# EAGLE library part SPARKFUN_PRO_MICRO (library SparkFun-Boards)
SparkFun Pro Micro Atmega32U4 compatible footprint. SparkFun Products: 3.3V/8MHz 5V/16MHz

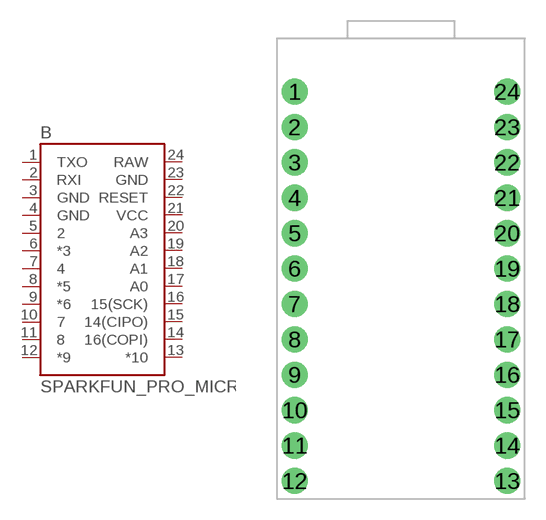
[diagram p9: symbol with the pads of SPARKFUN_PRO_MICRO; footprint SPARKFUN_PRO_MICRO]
Designator prefix B

## SPARKFUN_PRO_MICRO  [SPARKFUN_PRO_MICRO]
1  TXO
2  RXI
3  GND  pwr
4  GND  pwr
5  2
6  *3
7  4
8  *5
9  *6
10  7
11  8
12  *9
13  *10
14  16(COPI)
15  14(CIPO)
16  15(SCK)
17  A0
18  A1
19  A2
20  A3
21  VCC  pwr
22  RESET
23  GND  pwr
24  RAW  pwr

## Footprint SPARKFUN_PRO_MICRO (pad centres in mm)
SparkFun Pro Mico Footprint (with USB connector) Specifications: Pin count: 24 Pin pitch: 0.1" Area:0.7x1.3" Example device(s): SparkFun Pro Micro
drill 1.016 pad 1.88: 1 -7.62,12.7; 2 -7.62,10.16; 3 -7.62,7.62; 4 -7.62,5.08; 5 -7.62,2.54; 6 -7.62,0; 7 -7.62,-2.54; 8 -7.62,-5.08; 9 -7.62,-7.62; 10 -7.62,-10.16; 11 -7.62,-12.7; 12 -7.62,-15.24; 13 7.62,-15.24; 14 7.62,-12.7; 15 7.62,-10.16; 16 7.62,-7.62; 17 7.62,-5.08; 18 7.62,-2.54; 19 7.62,0; 20 7.62,2.54; 21 7.62,5.08; 22 7.62,7.62; 23 7.62,10.16; 24 7.62,12.7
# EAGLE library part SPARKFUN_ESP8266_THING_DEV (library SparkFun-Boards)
SparkFun Thing -Dev Board The SparkFun ESP8266 Thing Dev is a breakout and development board for the ESP8266 WiFi SoC, with an integrated FTDI USB-to-Serial chip. SparkFun Products: SparkFun ESP8266 Thing-Dev Board

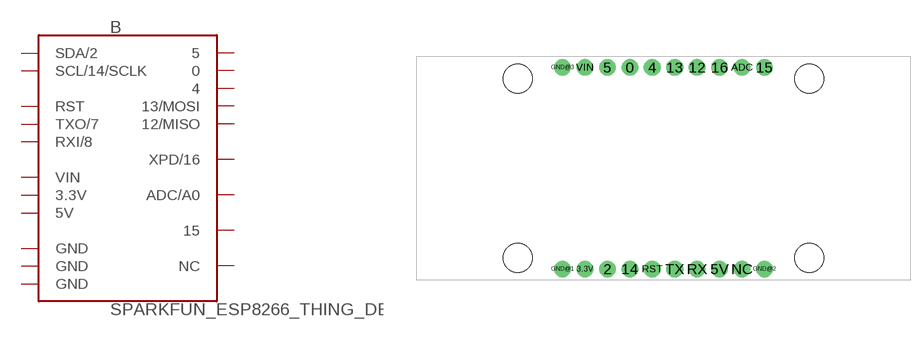
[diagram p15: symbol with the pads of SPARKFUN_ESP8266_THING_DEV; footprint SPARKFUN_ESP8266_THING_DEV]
Designator prefix B

## SPARKFUN_ESP8266_THING_DEV (SF_ID: WRL-13711)  [SPARKFUN_ESP8266_THING_DEV]
0  0
2  SDA/2
3.3V  3.3V  pwr
4  4
5  5
5V  5V  pwr
12  12/MISO
13  13/MOSI
14  SCL/14/SCLK
15  15
16  XPD/16
ADC  ADC/A0
GND@1  GND  pwr
GND@2  GND  pwr
GND@3  GND  pwr
NC  NC  nc
RST  RST  in
RX  RXI/8  in
TX  TXO/7  out
VIN  VIN  pwr

## Footprint SPARKFUN_ESP8266_THING_DEV (pad centres in mm)
SparkFun Thing Development Board Footprint Specifications: Pin count: 20 Pin pitch:0.1 inch Area: 2.2 x 1.0 inchees Example device(s): SparkFun Thing Development Board
drill 1.016 pad 1.88: 0 -2.54,11.43; 2 -5.08,-11.43; 3.3V -7.62,-11.43; 4 0,11.43; 5 -5.08,11.43; 5V 7.62,-11.43; 12 5.08,11.43; 13 2.54,11.43; 14 -2.54,-11.43; 15 12.7,11.43; 16 7.62,11.43; ADC 10.16,11.43; GND@1 -10.16,-11.43; GND@2 12.7,-11.43; GND@3 -10.16,11.43; NC 10.16,-11.43; RST 0,-11.43; RX 5.08,-11.43; TX 2.54,-11.43; VIN -7.62,11.43
hole 3.302 at -15.24,-10.16
hole 3.302 at -15.24,10.16
hole 3.302 at 17.78,10.16
hole 3.302 at 17.78,-10.16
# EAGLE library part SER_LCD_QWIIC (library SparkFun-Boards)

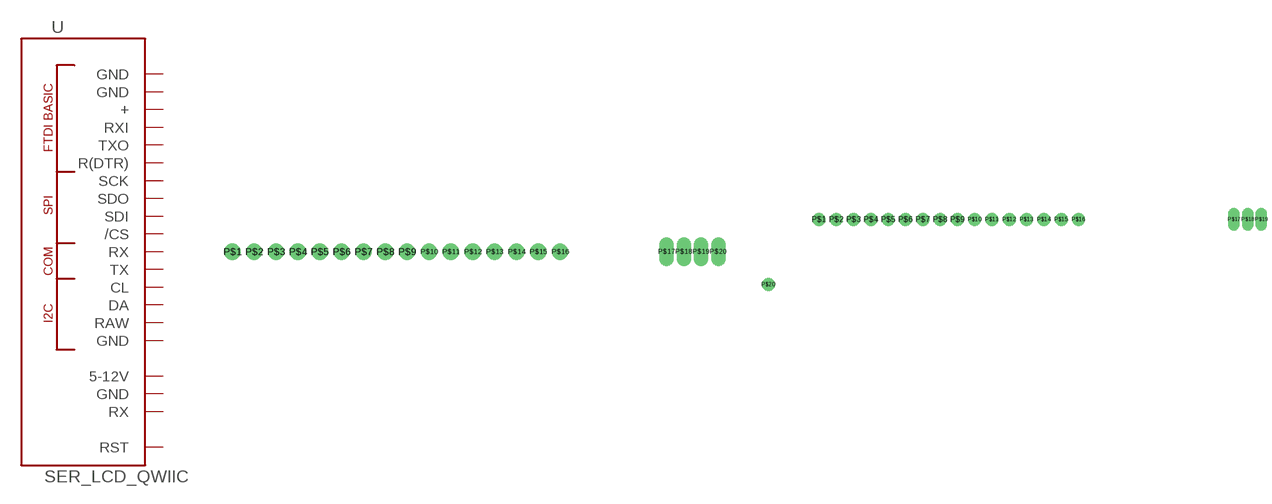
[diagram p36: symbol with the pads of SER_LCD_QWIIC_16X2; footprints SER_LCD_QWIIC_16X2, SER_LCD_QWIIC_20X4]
Designator prefix -

## SER_LCD_QWIIC16X2  [SER_LCD_QWIIC_16X2]
P$1  GND
P$2  GND
P$3  +
P$4  RXI
P$5  TXO
P$6  R(DTR)
P$7  SCK
P$8  SDO
P$9  SDI
P$10  /CS
P$11  RX
P$12  TX
P$13  CL
P$14  DA
P$15  RAW
P$16  GND
P$17  5-12V
P$18  GND
P$19  RX
P$20  RST

## SER_LCD_QWIIC20X4  [SER_LCD_QWIIC_20X4]
Pads as for SER_LCD_QWIIC_16X2

## Footprint SER_LCD_QWIIC_16X2 (pad centres in mm)
drill 1.118 pad 1.88: P$1 9.652,33.782; P$2 12.192,33.782; P$3 14.732,33.782; P$4 17.272,33.782; P$5 19.812,33.782; P$6 22.352,33.782; P$7 24.892,33.782; P$8 27.432,33.782; P$9 29.972,33.782; P$10 32.512,33.782; P$11 35.052,33.782; P$12 37.592,33.782; P$13 40.132,33.782; P$14 42.672,33.782; P$15 45.212,33.782; P$16 47.752,33.782
drill 1.118 pad 1.524 long: P$17 60.142,33.782; P$18 62.142,33.782; P$19 64.142,33.782; P$20 66.142,33.782

## Footprint SER_LCD_QWIIC_20X4 (pad centres in mm)
drill 1.118 pad 1.88: P$1 9.906,57.404; P$2 12.446,57.404; P$3 14.986,57.404; P$4 17.526,57.404; P$5 20.066,57.404; P$6 22.606,57.404; P$7 25.146,57.404; P$8 27.686,57.404; P$9 30.226,57.404; P$10 32.766,57.404; P$11 35.306,57.404; P$12 37.846,57.404; P$13 40.386,57.404; P$14 42.926,57.404; P$15 45.466,57.404; P$16 48.006,57.404; P$20 2.489,47.854
drill 1.118 pad 1.524 long: P$17 70.815,57.404; P$18 72.815,57.404; P$19 74.815,57.404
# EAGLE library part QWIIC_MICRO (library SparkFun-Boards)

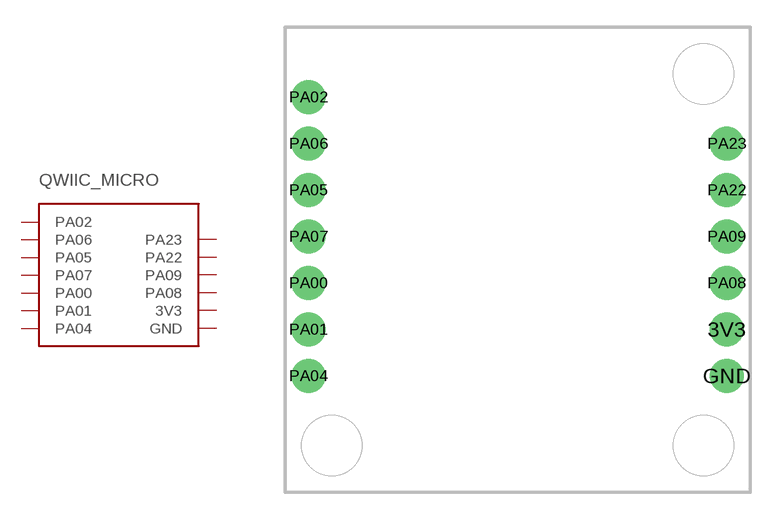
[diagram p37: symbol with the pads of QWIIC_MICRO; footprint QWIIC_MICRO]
Designator prefix -

## QWIIC_MICRO  [QWIIC_MICRO]
3V3  3V3
GND  GND
PA00  PA00
PA01  PA01
PA02  PA02
PA04  PA04
PA05  PA05
PA06  PA06
PA07  PA07
PA08  PA08
PA09  PA09
PA22  PA22
PA23  PA23

## Footprint QWIIC_MICRO (pad centres in mm)
drill 1.016 pad 1.88: 3V3 24.13,8.89; GND 24.13,6.35; PA00 1.27,11.43; PA01 1.27,8.89; PA02 1.27,21.59; PA04 1.27,6.35; PA05 1.27,16.51; PA06 1.27,19.05; PA07 1.27,13.97; PA08 24.13,11.43; PA09 24.13,13.97; PA22 24.13,16.51; PA23 24.13,19.05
